One B-rep face of a CAD part: STEP entity #1199.
In plain terms, the planar face has unit normal (-1, 0, 0).
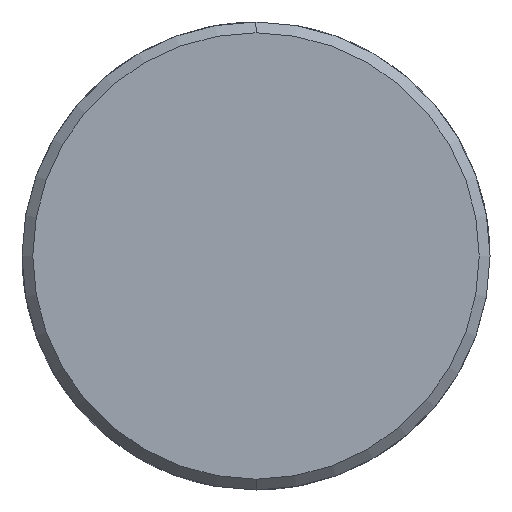
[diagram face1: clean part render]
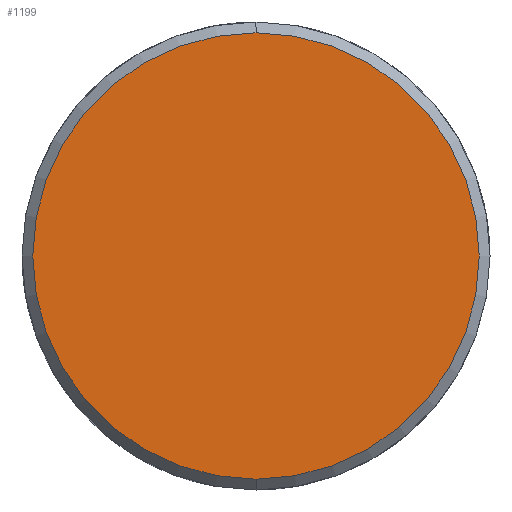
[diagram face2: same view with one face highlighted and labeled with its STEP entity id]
Its self-contained STEP definition (entity closure, numbers rounded to 3 decimals):
#1131=CARTESIAN_POINT('Vertex',(-10.,0.,-31.)) ;
#1134=CARTESIAN_POINT('Axis2P3D Location',(-10.,0.,0.)) ;
#1138=CARTESIAN_POINT('Vertex',(-10.,31.,0.)) ;
#1141=CARTESIAN_POINT('Axis2P3D Location',(-10.,0.,0.)) ;
#1145=CARTESIAN_POINT('Vertex',(-10.,0.,31.)) ;
#1167=CARTESIAN_POINT('Axis2P3D Location',(-10.,0.,0.)) ;
#1171=CARTESIAN_POINT('Vertex',(-10.,-31.,0.)) ;
#1174=CARTESIAN_POINT('Axis2P3D Location',(-10.,0.,0.)) ;
#1188=CARTESIAN_POINT('Axis2P3D Location',(-10.,0.,0.)) ;
#1135=DIRECTION('Axis2P3D Direction',(1.,0.,-0.)) ;
#1142=DIRECTION('Axis2P3D Direction',(1.,0.,-0.)) ;
#1168=DIRECTION('Axis2P3D Direction',(1.,0.,-0.)) ;
#1175=DIRECTION('Axis2P3D Direction',(1.,0.,-0.)) ;
#1189=DIRECTION('Axis2P3D Direction',(1.,0.,-0.)) ;
#1190=DIRECTION('Axis2P3D XDirection',(-0.,0.,-1.)) ;
#1136=AXIS2_PLACEMENT_3D('Circle Axis2P3D',#1134,#1135,$) ;
#1143=AXIS2_PLACEMENT_3D('Circle Axis2P3D',#1141,#1142,$) ;
#1169=AXIS2_PLACEMENT_3D('Circle Axis2P3D',#1167,#1168,$) ;
#1176=AXIS2_PLACEMENT_3D('Circle Axis2P3D',#1174,#1175,$) ;
#1191=AXIS2_PLACEMENT_3D('Plane Axis2P3D',#1188,#1189,#1190) ;
#1194=ORIENTED_EDGE('',*,*,#1140,.F.) ;
#1195=ORIENTED_EDGE('',*,*,#1178,.F.) ;
#1196=ORIENTED_EDGE('',*,*,#1173,.F.) ;
#1197=ORIENTED_EDGE('',*,*,#1147,.F.) ;
#1199=ADVANCED_FACE('351-50X96X220',(#1198),#1192,.F.) ;
#1137=CIRCLE('generated circle',#1136,31.) ;
#1144=CIRCLE('generated circle',#1143,31.) ;
#1170=CIRCLE('generated circle',#1169,31.) ;
#1177=CIRCLE('generated circle',#1176,31.) ;
#1140=EDGE_CURVE('',#1132,#1139,#1137,.T.) ;
#1147=EDGE_CURVE('',#1139,#1146,#1144,.T.) ;
#1173=EDGE_CURVE('',#1146,#1172,#1170,.T.) ;
#1178=EDGE_CURVE('',#1172,#1132,#1177,.T.) ;
#1193=EDGE_LOOP('',(#1194,#1195,#1196,#1197)) ;
#1198=FACE_OUTER_BOUND('',#1193,.T.) ;
#1192=PLANE('Plane',#1191) ;
#1132=VERTEX_POINT('',#1131) ;
#1139=VERTEX_POINT('',#1138) ;
#1146=VERTEX_POINT('',#1145) ;
#1172=VERTEX_POINT('',#1171) ;
